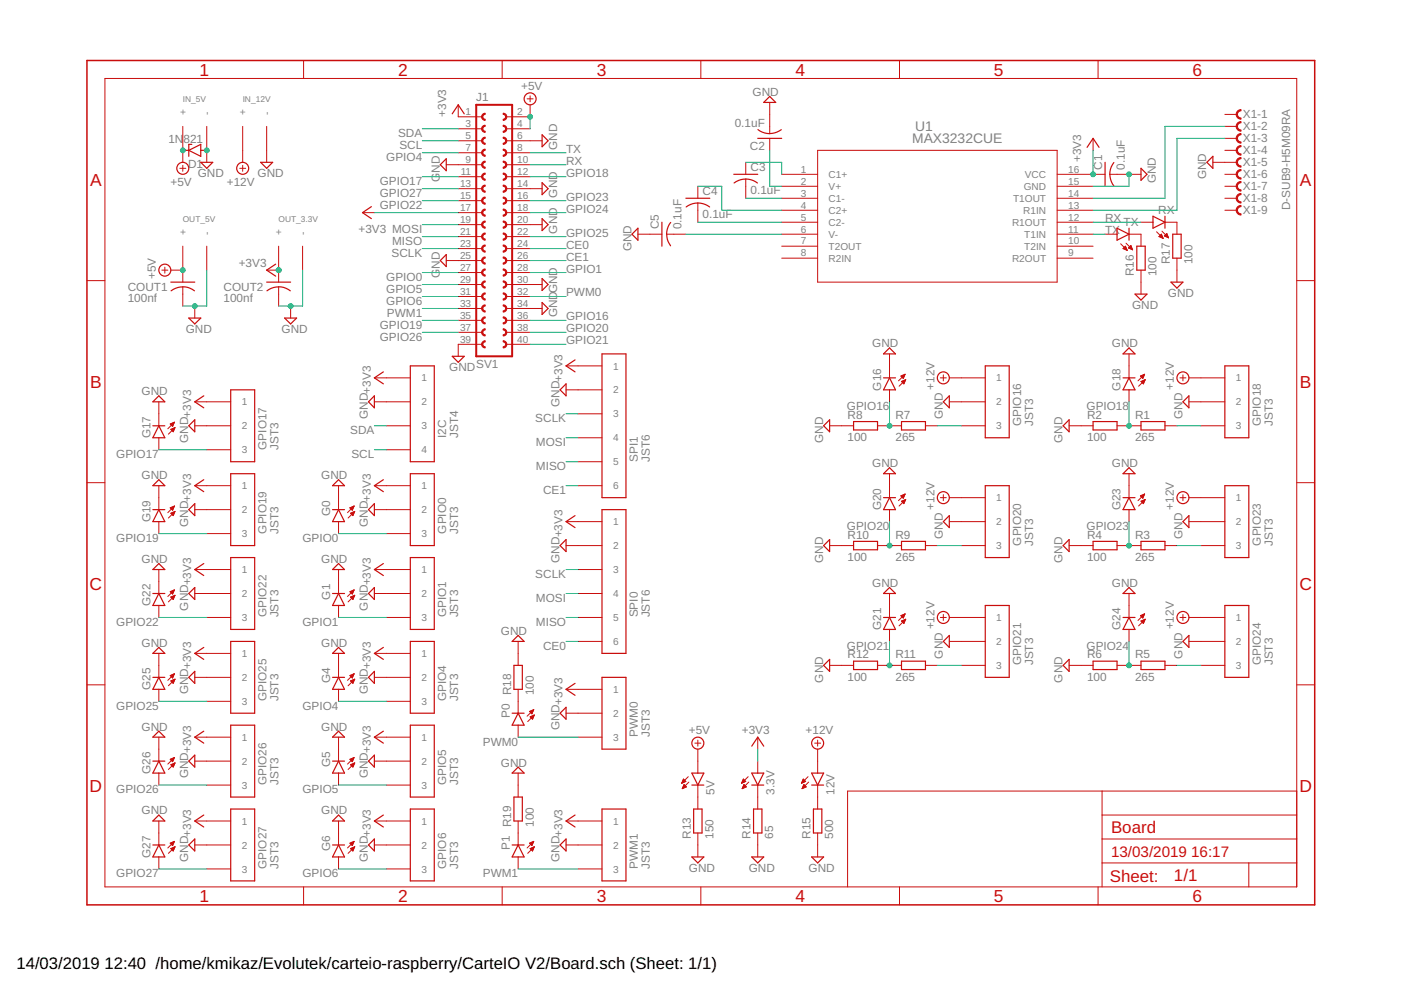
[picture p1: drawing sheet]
<svg xmlns="http://www.w3.org/2000/svg" width="297mm" height="210mm" viewBox="0 0 297 210" stroke-linecap="round" stroke-linejoin="round" font-family="sans-serif">
<defs><g id="words">
<g font-size="3.7" fill="#c90d0c">
<text x="42.3" y="16">1</text>
<text x="84.4" y="16">2</text>
<text x="126.5" y="16">3</text>
<text x="168.6" y="16">4</text>
<text x="210.7" y="16">5</text>
<text x="252.9" y="16">6</text>
<text x="19.1" y="39.4">A</text>
<text x="275.6" y="39.4">A</text>
<text x="19.1" y="82.2">B</text>
<text x="275.6" y="82.2">B</text>
<text x="19" y="125.1">C</text>
<text x="275.5" y="125.1">C</text>
<text x="19" y="167.9">D</text>
<text x="275.5" y="167.9">D</text>
<text x="42.3" y="191.2">1</text>
<text x="84.4" y="191.2">2</text>
<text x="126.5" y="191.2">3</text>
<text x="168.6" y="191.2">4</text>
<text x="210.7" y="191.2">5</text>
<text x="252.9" y="191.2">6</text>
</g>
<g font-size="3.6" fill="#c90d0c">
<text x="235.6" y="176.6">Board</text>
<text x="235.3" y="186.9">Sheet:</text>
<text x="248.9" y="186.8">1/1</text>
</g>
<g font-size="3.5">
<text x="3.5" y="205.4">14/03/2019</text>
<text x="22.2" y="205.4">12:40 /home/kmikaz/Evolutek/carteio-raspberry/CarteIO V2/Board.sch (Sheet: 1/1)</text>
</g>
<g font-size="3.2" fill="#c90d0c">
<text x="235.6" y="181.7">13/03/2019</text>
<text x="252.6" y="181.7">16:17</text>
</g>
<g font-size="2.9" fill="#808080">
<text x="194.1" y="27.8">U1</text>
<text x="193.4" y="30.4">MAX3232CUE</text>
</g>
<g font-size="2.5" fill="#808080">
<text x="101" y="21.5">J1</text>
<text x="110.5" y="19.1">+5V</text>
<text x="159.5" y="20.3">GND</text>
<text x="84.4" y="29.1">SDA</text>
<text x="94.6" y="24.8" transform="rotate(-90 94.6 24.8)">+3V3</text>
<text x="155.8" y="26.9">0.1uF</text>
<text x="263.5" y="25">X1-1</text>
<text x="263.5" y="27.6">X1-2</text>
<text x="35.7" y="30.2">1N</text>
<text x="38.9" y="30.2">821</text>
<text x="39.9" y="35.6">D1</text>
<text x="81.9" y="34.2">GPIO4</text>
<text x="84.7" y="31.6">SCL</text>
<text x="118.1" y="31.7" transform="rotate(-90 118.1 31.7)">GND</text>
<text x="120" y="32.4">TX</text>
<text x="120" y="34.9">RX</text>
<text x="159" y="31.7">C2</text>
<text x="229.2" y="34.4" transform="rotate(-90 229.2 34.4)">+3V3</text>
<text x="233.7" y="35.9" transform="rotate(-90 233.7 35.9)">C1</text>
<text x="238.5" y="35.9" transform="rotate(-90 238.5 35.9)">0.1uF</text>
<text x="263.5" y="30.1">X1-3</text>
<text x="263.5" y="32.6">X1-4</text>
<text x="263.5" y="35.2">X1-5</text>
<text x="36.1" y="39.4">+5V</text>
<text x="41.9" y="37.6">GND</text>
<text x="48.1" y="39.4">+12V</text>
<text x="54.6" y="37.6">GND</text>
<text x="80.5" y="39.2">GPIO17</text>
<text x="80.5" y="41.8">GPIO27</text>
<text x="93.2" y="38.6" transform="rotate(-90 93.2 38.6)">GND</text>
<text x="118.1" y="41.9" transform="rotate(-90 118.1 41.9)">GND</text>
<text x="120" y="37.5">GPIO18</text>
<text x="149" y="41.4">C4</text>
<text x="159.1" y="41.1">0.1uF</text>
<text x="159.1" y="36.3">C3</text>
<text x="245.1" y="38.9" transform="rotate(-90 245.1 38.9)">GND</text>
<text x="255.8" y="38.1" transform="rotate(-90 255.8 38.1)">GND</text>
<text x="263.5" y="37.7">X1-6</text>
<text x="263.5" y="40.3">X1-7</text>
<text x="80.5" y="44.3">GPIO22</text>
<text x="120" y="42.5">GPIO23</text>
<text x="120" y="45.1">GPIO24</text>
<text x="149" y="46.2">0.1uF</text>
<text x="234.3" y="47.1">RX</text>
<text x="238.2" y="47.9">TX</text>
<text x="245.6" y="45.3">RX</text>
<text x="263.5" y="42.8">X1-8</text>
<text x="263.5" y="45.3">X1-9</text>
<text x="273.5" y="44.6" transform="rotate(-90 273.5 44.6)">D-SUB9-H5M09RA</text>
<text x="76" y="49.4">+3V3 MOSI</text>
<text x="83.2" y="51.9">MISO</text>
<text x="118.1" y="49.5" transform="rotate(-90 118.1 49.5)">GND</text>
<text x="120" y="50.2">GPIO25</text>
<text x="120" y="52.7">CE0</text>
<text x="133.9" y="53.3" transform="rotate(-90 133.9 53.3)">GND</text>
<text x="139.7" y="48.6" transform="rotate(-90 139.7 48.6)">C5</text>
<text x="144.5" y="48.6" transform="rotate(-90 144.5 48.6)">0.1uF</text>
<text x="234.3" y="49.7">TX</text>
<text x="33" y="59.2" transform="rotate(-90 33 59.2)">+5V</text>
<text x="50.6" y="56.5">+3V3</text>
<text x="81.9" y="59.6">GPIO0</text>
<text x="83" y="54.5">SCLK</text>
<text x="93.2" y="58.9" transform="rotate(-90 93.2 58.9)">GND</text>
<text x="120" y="57.8">GPIO1</text>
<text x="120" y="55.2">CE1</text>
<text x="240.4" y="58.5" transform="rotate(-90 240.4 58.5)">R16</text>
<text x="245.2" y="58.5" transform="rotate(-90 245.2 58.5)">100</text>
<text x="248" y="56" transform="rotate(-90 248 56)">R17</text>
<text x="252.8" y="56" transform="rotate(-90 252.8 56)">100</text>
<text x="27.1" y="64">100nf</text>
<text x="27.1" y="61.7">COUT1</text>
<text x="47.4" y="64">100nf</text>
<text x="47.4" y="61.7">COUT2</text>
<text x="81.9" y="62.1">GPIO5</text>
<text x="81.9" y="64.6">GPIO6</text>
<text x="120" y="62.9">PWM0</text>
<text x="240" y="65.5">GND</text>
<text x="247.6" y="63">GND</text>
<text x="39.4" y="70.6">GND</text>
<text x="59.7" y="70.6">GND</text>
<text x="80.5" y="69.7">GPIO19</text>
<text x="82.1" y="67.2">PWM1</text>
<text x="118.1" y="67.3" transform="rotate(-90 118.1 67.3)">GNDGND</text>
<text x="120" y="67.9">GPIO16</text>
<text x="120" y="70.5">GPIO20</text>
<text x="80.5" y="72.3">GPIO26</text>
<text x="120" y="73">GPIO21</text>
<text x="184.9" y="73.6">GND</text>
<text x="235.7" y="73.6">GND</text>
<text x="30" y="83.8">GND</text>
<text x="78.6" y="83.5" transform="rotate(-90 78.6 83.5)">+3V3</text>
<text x="95.3" y="78.7">GND</text>
<text x="101" y="78.1">SV1</text>
<text x="119.3" y="81" transform="rotate(-90 119.3 81)">+3V3</text>
<text x="186.8" y="82.8" transform="rotate(-90 186.8 82.8)">G16</text>
<text x="198.1" y="82.7" transform="rotate(-90 198.1 82.7)">+12V</text>
<text x="237.6" y="82.8" transform="rotate(-90 237.6 82.8)">G18</text>
<text x="248.9" y="82.7" transform="rotate(-90 248.9 82.7)">+12V</text>
<text x="40.5" y="88.6" transform="rotate(-90 40.5 88.6)">+3V3</text>
<text x="78" y="88.8" transform="rotate(-90 78 88.8)">GND</text>
<text x="113.5" y="89.5">SCLK</text>
<text x="118.6" y="86.3" transform="rotate(-90 118.6 86.3)">GND</text>
<text x="179.6" y="87">GPIO16</text>
<text x="179.7" y="88.8">R8</text>
<text x="189.9" y="88.8">R7</text>
<text x="199.9" y="88.8" transform="rotate(-90 199.9 88.8)">GND</text>
<text x="230.4" y="87">GPIO18</text>
<text x="230.5" y="88.8">R2</text>
<text x="240.6" y="88.8">R1</text>
<text x="250.7" y="88.8" transform="rotate(-90 250.7 88.8)">GND</text>
<text x="31.9" y="93" transform="rotate(-90 31.9 93)">G17</text>
<text x="39.9" y="93.9" transform="rotate(-90 39.9 93.9)">GND</text>
<text x="56.5" y="95.4" transform="rotate(-90 56.5 95.4)">GPIO17</text>
<text x="59.1" y="95.4" transform="rotate(-90 59.1 95.4)">JST3</text>
<text x="74.2" y="92.1">SDA</text>
<text x="94.6" y="92.8" transform="rotate(-90 94.6 92.8)">I2C</text>
<text x="97.2" y="92.8" transform="rotate(-90 97.2 92.8)">JST4</text>
<text x="113.6" y="94.6">MOSI</text>
<text x="174.5" y="93.9" transform="rotate(-90 174.5 93.9)">GND</text>
<text x="179.7" y="93.6">100</text>
<text x="189.9" y="93.6">265</text>
<text x="216.5" y="90.3" transform="rotate(-90 216.5 90.3)">GPIO16</text>
<text x="219.1" y="90.3" transform="rotate(-90 219.1 90.3)">JST3</text>
<text x="225.3" y="93.9" transform="rotate(-90 225.3 93.9)">GND</text>
<text x="230.5" y="93.6">100</text>
<text x="240.6" y="93.6">265</text>
<text x="267.3" y="90.3" transform="rotate(-90 267.3 90.3)">GPIO18</text>
<text x="269.9" y="90.3" transform="rotate(-90 269.9 90.3)">JST3</text>
<text x="24.7" y="97.1">GPIO17</text>
<text x="30" y="101.6">GND</text>
<text x="68.1" y="101.6">GND</text>
<text x="74.5" y="97.1">SCL</text>
<text x="113.6" y="99.7">MISO</text>
<text x="135.3" y="97.9" transform="rotate(-90 135.3 97.9)">SPI1</text>
<text x="137.8" y="97.9" transform="rotate(-90 137.8 97.9)">JST6</text>
<text x="184.9" y="99">GND</text>
<text x="235.7" y="99">GND</text>
<text x="40.5" y="106.3" transform="rotate(-90 40.5 106.3)">+3V3</text>
<text x="78.6" y="106.3" transform="rotate(-90 78.6 106.3)">+3V3</text>
<text x="115.1" y="104.8">CE1</text>
<text x="31.9" y="110.7" transform="rotate(-90 31.9 110.7)">G19</text>
<text x="39.9" y="111.7" transform="rotate(-90 39.9 111.7)">GND</text>
<text x="56.5" y="113.1" transform="rotate(-90 56.5 113.1)">GPIO19</text>
<text x="59.1" y="113.1" transform="rotate(-90 59.1 113.1)">JST3</text>
<text x="70" y="109.3" transform="rotate(-90 70 109.3)">G0</text>
<text x="78" y="111.7" transform="rotate(-90 78 111.7)">GND</text>
<text x="94.6" y="113.1" transform="rotate(-90 94.6 113.1)">GPIO0</text>
<text x="97.2" y="113.1" transform="rotate(-90 97.2 113.1)">JST3</text>
<text x="119.3" y="114" transform="rotate(-90 119.3 114)">+3V3</text>
<text x="179.6" y="112.4">GPIO20</text>
<text x="186.8" y="108.2" transform="rotate(-90 186.8 108.2)">G20</text>
<text x="198.1" y="108.1" transform="rotate(-90 198.1 108.1)">+12V</text>
<text x="230.4" y="112.4">GPIO23</text>
<text x="237.6" y="108.2" transform="rotate(-90 237.6 108.2)">G23</text>
<text x="248.9" y="108.1" transform="rotate(-90 248.9 108.1)">+12V</text>
<text x="24.7" y="114.9">GPIO19</text>
<text x="30" y="119.4">GND</text>
<text x="64.1" y="114.9">GPIO0</text>
<text x="68.1" y="119.4">GND</text>
<text x="118.6" y="119.3" transform="rotate(-90 118.6 119.3)">GND</text>
<text x="174.5" y="119.3" transform="rotate(-90 174.5 119.3)">GND</text>
<text x="179.7" y="119">100</text>
<text x="179.7" y="114.2">R10</text>
<text x="189.9" y="119">265</text>
<text x="189.9" y="114.2">R9</text>
<text x="199.9" y="114.2" transform="rotate(-90 199.9 114.2)">GND</text>
<text x="216.5" y="115.7" transform="rotate(-90 216.5 115.7)">GPIO20</text>
<text x="219.1" y="115.7" transform="rotate(-90 219.1 115.7)">JST3</text>
<text x="225.3" y="119.3" transform="rotate(-90 225.3 119.3)">GND</text>
<text x="230.5" y="119">100</text>
<text x="230.5" y="114.2">R4</text>
<text x="240.6" y="119">265</text>
<text x="240.6" y="114.2">R3</text>
<text x="250.7" y="114.2" transform="rotate(-90 250.7 114.2)">GND</text>
<text x="267.3" y="115.7" transform="rotate(-90 267.3 115.7)">GPIO23</text>
<text x="269.9" y="115.7" transform="rotate(-90 269.9 115.7)">JST3</text>
<text x="40.5" y="124.1" transform="rotate(-90 40.5 124.1)">+3V3</text>
<text x="78.6" y="124.1" transform="rotate(-90 78.6 124.1)">+3V3</text>
<text x="113.5" y="122.5">SCLK</text>
<text x="184.9" y="124.4">GND</text>
<text x="235.7" y="124.4">GND</text>
<text x="31.9" y="128.5" transform="rotate(-90 31.9 128.5)">G22</text>
<text x="39.9" y="129.5" transform="rotate(-90 39.9 129.5)">GND</text>
<text x="56.5" y="130.9" transform="rotate(-90 56.5 130.9)">GPIO22</text>
<text x="59.1" y="130.9" transform="rotate(-90 59.1 130.9)">JST3</text>
<text x="70" y="127.1" transform="rotate(-90 70 127.1)">G1</text>
<text x="78" y="129.5" transform="rotate(-90 78 129.5)">GND</text>
<text x="94.6" y="130.9" transform="rotate(-90 94.6 130.9)">GPIO1</text>
<text x="97.2" y="130.9" transform="rotate(-90 97.2 130.9)">JST3</text>
<text x="113.6" y="127.6">MOSI</text>
<text x="135.3" y="130.9" transform="rotate(-90 135.3 130.9)">SPI0</text>
<text x="137.8" y="130.9" transform="rotate(-90 137.8 130.9)">JST6</text>
<text x="24.7" y="132.7">GPIO22</text>
<text x="30" y="137.1">GND</text>
<text x="64.1" y="132.7">GPIO1</text>
<text x="68.1" y="137.1">GND</text>
<text x="106.2" y="134.6">GND</text>
<text x="113.6" y="132.7">MISO</text>
<text x="115.1" y="137.8">CE0</text>
<text x="179.6" y="137.8">GPIO21</text>
<text x="186.8" y="133.6" transform="rotate(-90 186.8 133.6)">G21</text>
<text x="198.1" y="133.4" transform="rotate(-90 198.1 133.4)">+12V</text>
<text x="230.4" y="137.8">GPIO24</text>
<text x="237.6" y="133.6" transform="rotate(-90 237.6 133.6)">G24</text>
<text x="248.9" y="133.4" transform="rotate(-90 248.9 133.4)">+12V</text>
<text x="40.5" y="141.9" transform="rotate(-90 40.5 141.9)">+3V3</text>
<text x="78.6" y="141.9" transform="rotate(-90 78.6 141.9)">+3V3</text>
<text x="179.7" y="139.6">R12</text>
<text x="189.9" y="139.6">R11</text>
<text x="199.9" y="139.6" transform="rotate(-90 199.9 139.6)">GND</text>
<text x="216.5" y="141.1" transform="rotate(-90 216.5 141.1)">GPIO21</text>
<text x="219.1" y="141.1" transform="rotate(-90 219.1 141.1)">JST3</text>
<text x="230.5" y="139.6">R6</text>
<text x="240.6" y="139.6">R5</text>
<text x="250.7" y="139.6" transform="rotate(-90 250.7 139.6)">GND</text>
<text x="267.3" y="141.1" transform="rotate(-90 267.3 141.1)">GPIO24</text>
<text x="269.9" y="141.1" transform="rotate(-90 269.9 141.1)">JST3</text>
<text x="31.9" y="146.3" transform="rotate(-90 31.9 146.3)">G25</text>
<text x="39.9" y="147.2" transform="rotate(-90 39.9 147.2)">GND</text>
<text x="56.5" y="148.7" transform="rotate(-90 56.5 148.7)">GPIO25</text>
<text x="59.1" y="148.7" transform="rotate(-90 59.1 148.7)">JST3</text>
<text x="70" y="144.9" transform="rotate(-90 70 144.9)">G4</text>
<text x="78" y="147.2" transform="rotate(-90 78 147.2)">GND</text>
<text x="94.6" y="148.7" transform="rotate(-90 94.6 148.7)">GPIO4</text>
<text x="97.2" y="148.7" transform="rotate(-90 97.2 148.7)">JST3</text>
<text x="108.4" y="147.4" transform="rotate(-90 108.4 147.4)">R18</text>
<text x="113.2" y="147.4" transform="rotate(-90 113.2 147.4)">100</text>
<text x="119.3" y="149.5" transform="rotate(-90 119.3 149.5)">+3V3</text>
<text x="174.5" y="144.7" transform="rotate(-90 174.5 144.7)">GND</text>
<text x="179.7" y="144.4">100</text>
<text x="189.9" y="144.4">265</text>
<text x="225.3" y="144.7" transform="rotate(-90 225.3 144.7)">GND</text>
<text x="230.5" y="144.4">100</text>
<text x="240.6" y="144.4">265</text>
<text x="24.7" y="150.5">GPIO25</text>
<text x="30" y="154.9">GND</text>
<text x="64.1" y="150.5">GPIO4</text>
<text x="68.1" y="154.9">GND</text>
<text x="108.1" y="152.2" transform="rotate(-90 108.1 152.2)">P0</text>
<text x="118.6" y="154.9" transform="rotate(-90 118.6 154.9)">GND</text>
<text x="146" y="155.7">+5V</text>
<text x="157.3" y="155.5">+3V3</text>
<text x="170.8" y="155.7">+12V</text>
<text x="40.5" y="159.7" transform="rotate(-90 40.5 159.7)">+3V3</text>
<text x="78.6" y="159.7" transform="rotate(-90 78.6 159.7)">+3V3</text>
<text x="102.4" y="158.1">PWM0</text>
<text x="135.3" y="156.3" transform="rotate(-90 135.3 156.3)">PWM0</text>
<text x="137.8" y="156.3" transform="rotate(-90 137.8 156.3)">JST3</text>
<text x="31.9" y="164.1" transform="rotate(-90 31.9 164.1)">G26</text>
<text x="39.9" y="165" transform="rotate(-90 39.9 165)">GND</text>
<text x="56.5" y="166.5" transform="rotate(-90 56.5 166.5)">GPIO26</text>
<text x="59.1" y="166.5" transform="rotate(-90 59.1 166.5)">JST3</text>
<text x="70" y="162.7" transform="rotate(-90 70 162.7)">G5</text>
<text x="78" y="165" transform="rotate(-90 78 165)">GND</text>
<text x="94.6" y="166.5" transform="rotate(-90 94.6 166.5)">GPIO5</text>
<text x="97.2" y="166.5" transform="rotate(-90 97.2 166.5)">JST3</text>
<text x="106.2" y="162.5">GND</text>
<text x="24.7" y="168.2">GPIO26</text>
<text x="30" y="172.7">GND</text>
<text x="64.1" y="168.2">GPIO5</text>
<text x="68.1" y="172.7">GND</text>
<text x="151.5" y="168.5" transform="rotate(-90 151.5 168.5)">5V</text>
<text x="164.2" y="168.5" transform="rotate(-90 164.2 168.5)">3.3V</text>
<text x="176.9" y="168.5" transform="rotate(-90 176.9 168.5)">12V</text>
<text x="40.5" y="177.4" transform="rotate(-90 40.5 177.4)">+3V3</text>
<text x="78.6" y="177.4" transform="rotate(-90 78.6 177.4)">+3V3</text>
<text x="108.4" y="175.3" transform="rotate(-90 108.4 175.3)">R19</text>
<text x="113.2" y="175.3" transform="rotate(-90 113.2 175.3)">100</text>
<text x="119.3" y="177.4" transform="rotate(-90 119.3 177.4)">+3V3</text>
<text x="146.5" y="177.9" transform="rotate(-90 146.5 177.9)">R13</text>
<text x="151.3" y="177.9" transform="rotate(-90 151.3 177.9)">150</text>
<text x="159.2" y="177.9" transform="rotate(-90 159.2 177.9)">R14</text>
<text x="164" y="177.9" transform="rotate(-90 164 177.9)">65</text>
<text x="171.9" y="177.9" transform="rotate(-90 171.9 177.9)">R15</text>
<text x="176.7" y="177.9" transform="rotate(-90 176.7 177.9)">500</text>
<text x="31.9" y="181.8" transform="rotate(-90 31.9 181.8)">G27</text>
<text x="39.9" y="182.8" transform="rotate(-90 39.9 182.8)">GND</text>
<text x="56.5" y="184.2" transform="rotate(-90 56.5 184.2)">GPIO27</text>
<text x="59.1" y="184.2" transform="rotate(-90 59.1 184.2)">JST3</text>
<text x="70" y="180.4" transform="rotate(-90 70 180.4)">G6</text>
<text x="78" y="182.8" transform="rotate(-90 78 182.8)">GND</text>
<text x="94.6" y="184.2" transform="rotate(-90 94.6 184.2)">GPIO6</text>
<text x="97.2" y="184.2" transform="rotate(-90 97.2 184.2)">JST3</text>
<text x="108.1" y="180.2" transform="rotate(-90 108.1 180.2)">P1</text>
<text x="118.6" y="182.8" transform="rotate(-90 118.6 182.8)">GND</text>
<text x="135.3" y="184.2" transform="rotate(-90 135.3 184.2)">PWM1</text>
<text x="137.8" y="184.2" transform="rotate(-90 137.8 184.2)">JST3</text>
<text x="146" y="184.9">GND</text>
<text x="158.7" y="184.9">GND</text>
<text x="171.4" y="184.9">GND</text>
<text x="24.7" y="186">GPIO27</text>
<text x="64.1" y="186">GPIO6</text>
<text x="102.4" y="186">PWM1</text>
</g>
<g font-size="2.1" fill="#808080">
<text x="39.5" y="24.5" transform="rotate(-90 39.5 24.5)">+</text>
<text x="44.6" y="24.5" transform="rotate(-90 44.6 24.5)">-</text>
<text x="52.2" y="24.5" transform="rotate(-90 52.2 24.5)">+</text>
<text x="57.3" y="24.5" transform="rotate(-90 57.3 24.5)">-</text>
<text x="98.7" y="24.4">1</text>
<text x="98.7" y="26.9">3</text>
<text x="98.7" y="29.5">5</text>
<text x="109.7" y="24.4">2</text>
<text x="109.7" y="26.9">4</text>
<text x="109.7" y="29.5">6</text>
<text x="98.7" y="32">7</text>
<text x="98.7" y="34.6">9</text>
<text x="109.7" y="32">8</text>
<text x="109.7" y="34.6">10</text>
<text x="97.5" y="39.6">13</text>
<text x="97.7" y="37.1">11</text>
<text x="109.7" y="37.1">12</text>
<text x="109.7" y="39.6">14</text>
<text x="169.8" y="36.6">1</text>
<text x="169.8" y="39.1">2</text>
<text x="169.8" y="41.7">3</text>
<text x="175.7" y="37.7">C1+</text>
<text x="175.7" y="40.3">V+</text>
<text x="217.1" y="40.3">GND</text>
<text x="217.3" y="37.7">VCC</text>
<text x="226.5" y="41.7">14</text>
<text x="226.5" y="39.1">15</text>
<text x="226.5" y="36.6">16</text>
<text x="97.5" y="42.2">15</text>
<text x="97.5" y="44.7">17</text>
<text x="97.5" y="47.3">19</text>
<text x="109.7" y="42.2">16</text>
<text x="109.7" y="44.7">18</text>
<text x="109.7" y="47.3">20</text>
<text x="169.8" y="44.2">4</text>
<text x="169.8" y="46.8">5</text>
<text x="175.7" y="42.8">C1-</text>
<text x="175.7" y="45.3">C2+</text>
<text x="175.7" y="47.9">C2-</text>
<text x="214.6" y="47.9">R1OUT</text>
<text x="214.8" y="42.8">T1OUT</text>
<text x="216.9" y="45.3">R1IN</text>
<text x="226.5" y="46.8">12</text>
<text x="226.5" y="44.2">13</text>
<text x="39.5" y="49.9" transform="rotate(-90 39.5 49.9)">+</text>
<text x="44.6" y="49.9" transform="rotate(-90 44.6 49.9)">-</text>
<text x="59.8" y="49.9" transform="rotate(-90 59.8 49.9)">+</text>
<text x="64.9" y="49.9" transform="rotate(-90 64.9 49.9)">-</text>
<text x="97.5" y="49.8">21</text>
<text x="97.5" y="52.3">23</text>
<text x="109.7" y="49.8">22</text>
<text x="109.7" y="52.3">24</text>
<text x="169.8" y="49.3">6</text>
<text x="169.8" y="51.8">7</text>
<text x="175.7" y="50.4">V-</text>
<text x="175.7" y="53">T2OUT</text>
<text x="217.2" y="53">T2IN</text>
<text x="217.2" y="50.4">T1IN</text>
<text x="226.5" y="51.8">10</text>
<text x="226.5" y="49.3">11</text>
<text x="97.5" y="54.9">25</text>
<text x="97.5" y="57.4">27</text>
<text x="97.5" y="60">29</text>
<text x="109.7" y="54.9">26</text>
<text x="109.7" y="57.4">28</text>
<text x="109.7" y="60">30</text>
<text x="169.8" y="54.4">8</text>
<text x="175.7" y="55.5">R2IN</text>
<text x="214.6" y="55.5">R2OUT</text>
<text x="226.5" y="54.4">9</text>
<text x="97.5" y="62.5">31</text>
<text x="97.5" y="65">33</text>
<text x="109.7" y="62.5">32</text>
<text x="109.7" y="65">34</text>
<text x="97.5" y="67.6">35</text>
<text x="97.5" y="70.1">37</text>
<text x="109.7" y="67.6">36</text>
<text x="109.7" y="70.1">38</text>
<text x="97.5" y="72.7">39</text>
<text x="109.7" y="72.7">40</text>
<text x="89.3" y="80.9">1</text>
<text x="130" y="78.3">1</text>
<text x="130" y="83.4">2</text>
<text x="211.2" y="80.9">1</text>
<text x="262" y="80.9">1</text>
<text x="51.2" y="86">1</text>
<text x="89.3" y="86">2</text>
<text x="130" y="88.5">3</text>
<text x="211.2" y="86">2</text>
<text x="262" y="86">2</text>
<text x="51.2" y="91">2</text>
<text x="89.3" y="91">3</text>
<text x="130" y="93.6">4</text>
<text x="211.2" y="91">3</text>
<text x="262" y="91">3</text>
<text x="51.2" y="96.1">3</text>
<text x="89.3" y="96.1">4</text>
<text x="130" y="98.7">5</text>
<text x="51.2" y="103.7">1</text>
<text x="89.3" y="103.7">1</text>
<text x="130" y="103.7">6</text>
<text x="211.2" y="106.3">1</text>
<text x="262" y="106.3">1</text>
<text x="51.2" y="108.8">2</text>
<text x="51.2" y="113.9">3</text>
<text x="89.3" y="108.8">2</text>
<text x="89.3" y="113.9">3</text>
<text x="130" y="111.4">1</text>
<text x="211.2" y="111.4">2</text>
<text x="262" y="111.4">2</text>
<text x="130" y="116.4">2</text>
<text x="211.2" y="116.4">3</text>
<text x="262" y="116.4">3</text>
<text x="51.2" y="121.5">1</text>
<text x="89.3" y="121.5">1</text>
<text x="130" y="121.5">3</text>
<text x="51.2" y="126.6">2</text>
<text x="51.2" y="131.7">3</text>
<text x="89.3" y="126.6">2</text>
<text x="89.3" y="131.7">3</text>
<text x="130" y="126.6">4</text>
<text x="130" y="131.7">5</text>
<text x="211.2" y="131.7">1</text>
<text x="262" y="131.7">1</text>
<text x="130" y="136.8">6</text>
<text x="211.2" y="136.8">2</text>
<text x="262" y="136.8">2</text>
<text x="51.2" y="139.3">1</text>
<text x="89.3" y="139.3">1</text>
<text x="211.2" y="141.8">3</text>
<text x="262" y="141.8">3</text>
<text x="51.2" y="144.4">2</text>
<text x="51.2" y="149.4">3</text>
<text x="89.3" y="144.4">2</text>
<text x="89.3" y="149.4">3</text>
<text x="130" y="146.9">1</text>
<text x="130" y="152">2</text>
<text x="51.2" y="157.1">1</text>
<text x="89.3" y="157.1">1</text>
<text x="130" y="157.1">3</text>
<text x="51.2" y="162.1">2</text>
<text x="51.2" y="167.2">3</text>
<text x="89.3" y="162.1">2</text>
<text x="89.3" y="167.2">3</text>
<text x="51.2" y="174.8">1</text>
<text x="51.2" y="179.9">2</text>
<text x="89.3" y="174.8">1</text>
<text x="89.3" y="179.9">2</text>
<text x="130" y="174.8">1</text>
<text x="130" y="179.9">2</text>
<text x="51.2" y="185">3</text>
<text x="89.3" y="185">3</text>
<text x="130" y="185">3</text>
</g>
<g font-size="1.8" fill="#808080">
<text x="38.8" y="21.7">IN_5V</text>
<text x="51.5" y="21.7">IN_12V</text>
<text x="38.8" y="47.1">OUT_5V</text>
<text x="59.1" y="47.1">OUT_3.3V</text>
</g>
</g></defs>
<g fill="none" stroke="#c90d0c" stroke-width=".21">
<path d="M22.2 16.6h252.7v171.4h-252.7zM64.4 12.8v3.8M106.5 12.8v3.8M148.6 12.8v3.8M190.7 12.8v3.8M232.8 12.8v3.8M38.1 35.7h1.3M38.8 26.8v7.6M38.8 35.1v1.2M43.8 26.8v7.6M50.8 35.7h1.3M51.5 26.8v7.6"/>
<path d="M51.5 35.1v1.2M56.5 26.8v7.6M94.6 34.9h7.6M97.2 22.2v2.6h5M97.2 29.8h5M97.2 27.3h5M97.2 32.4h5M97.2 37.5h5M107.3 29.8h7.6M107.3 27.3h5.1M107.3 32.4h5.1M107.3 34.9h5.1"/>
<path d="M107.3 37.5h5.1M111.8 21h1.2M112.4 20.3v1.3M112.4 22.2v2.6h-5.1M148 39.5v2.5M158.1 34.4v2.6M158.1 38v4M163.2 21.7v6.6M163.2 29.3v2.6M165.7 37h7.7M165.7 39.5h7.7M173.4 31.9h50.7v27.9h-50.7z"/>
<path d="M224.1 37h10.2M224.1 39.5h7.7M231.8 29.3v2.6M235.3 37h6.6M257.2 34.4h5M259.7 37h2.5M259.7 31.9h2.5M259.7 39.5h2.5M259.7 24.3h2.5M259.7 26.8h2.5M259.7 29.3h2.5M18.4 59.5h3.8"/>
<path d="M34.3 57.3h1.3M34.9 56.6v1.3M36.2 57.3h2.6M38.8 52.2v7.6M43.8 52.2v5.1M56.5 57.3h2.6M59.1 52.2v7.6M64.2 52.2v5.1M76.9 45.1h2.5M94.6 55.2h7.6M97.2 40h5M97.2 42.5h5"/>
<path d="M97.2 45.1h5M97.2 47.6h5M97.2 50.2h5M97.2 52.7h5M97.2 57.8h5M107.3 40h7.6M107.3 42.5h5.1M107.3 45.1h5.1M107.3 47.6h7.6M107.3 50.2h5.1M107.3 52.7h5.1M107.3 55.2h5.1"/>
<path d="M107.3 57.8h5.1M135.3 49.7h5M141.4 49.7h4M148 43.1v4M165.7 42h7.7M165.7 44.6h7.7M165.7 47.1h7.7M165.7 49.7h7.7M165.7 52.2h7.7M165.7 54.7h7.7M224.1 42h7.7M224.1 44.6h7.7"/>
<path d="M224.1 47.1h7.7M224.1 49.7h7.7M224.1 52.2h7.7M224.1 54.7h7.7M234.3 49.7h2.5M237.6 51.7l1.4 1.4M238.1 52.7l.5-.5 .4 .9zM238.1 52.7h.7M238.3 52.6h.5M238.3 52.8h.6M238.4 52.4h.3M238.5 52.3h.2"/>
<path d="M238.6 52.9h.3M238.7 51.6l1.4 1.4M238.9 53h.1M239.2 52.6l.9 .4M239.3 52.6h.7M239.4 49.7h2.5v2.5M239.4 52.4h.5M239.5 52.7h.5M239.5 52.3h.4M239.6 52.2h.2M239.8 52.8h.3M239.8 52.1l-.6 .5"/>
<path d="M239.8 52.1l.3 .9M239.8 52.1h.1M240 52.9h.1M241.9 47.1h2.6M241.9 57.3v5.1M245.2 49.1l1.4 1.4M245.7 50.2l.9 .3M245.7 50.1h.7M245.9 50h.5M246 50.2h.5M246 49.9h.3M246.1 49.8h.2"/>
<path d="M246.2 49.7l-.5 .5M246.2 49.7l.4 .8M246.2 50.4h.3M246.2 49.7h.1M246.4 49l1.4 1.4M246.5 50.5h.1M246.9 50h.7M247 47.1h2.5v2.6M247 49.9h.5M247.1 50.1h.5M247.1 49.8h.4M247.2 49.7h.2"/>
<path d="M247.4 49.5l-.5 .5 .9 .4M247.4 49.5l.4 .9M247.4 49.5v.1M247.4 50.2h.3M247.7 50.4h.1M249.5 54.7v5.1M259.7 42h2.5M259.7 44.6h2.5M274.9 59.5h3.8M38.8 60.8v4.1M41.3 64.9v2.5M59.1 60.8v4.1"/>
<path d="M61.6 64.9v2.5M97.2 60.3h5M97.2 62.9h5M97.2 65.4h5M97.2 67.9h5M97.2 70.5h5M102.2 73h-5v2.5M107.3 60.3h7.6M107.3 62.9h5.1M107.3 65.4h7.6M107.3 67.9h5.1M107.3 70.5h5.1"/>
<path d="M107.3 73h5.1M120 77.6h7.6M188.6 75v5.1M191 79.7l.9-.3-.4 .8zM191.1 79.8h.6M191.1 79.7h.6M191.2 79.9h.4M191.4 79.6h.4M191.7 79.4h.2M191.9 79.4l-1.4 1.4M200 79.5v1.3M239.4 75v5.1"/>
<path d="M241.8 79.7l.9-.3-.4 .8zM241.9 79.8h.6M241.9 79.7h.6M242 79.9h.4M242.2 79.6h.4M242.5 79.4h.1M242.7 79.4l-1.4 1.4M250.8 79.5v1.3M33.7 85.2v5.1M33.7 92.8v2.6M36.1 89.9l.9-.4-.4 .9zM36.1 89.9h.7"/>
<path d="M36.2 91l.9-.3-.4 .8zM36.2 90.1h.5M36.3 91h.7M36.3 89.8h.6M36.3 91.1h.6M36.4 90.2h.3M36.4 91.3h.5M36.5 90.3h.1M36.5 90.9h.5M36.6 91.4h.2M36.6 89.7h.3M36.7 91.5h.1"/>
<path d="M36.8 90.8h.2M36.9 89.6h.1M37 89.5l-1.4 1.4M37.1 90.7l-1.4 1.4M41.3 85.2h7.6M41.3 90.3h7.6M43.8 95.4h5.1M79.4 80.1h7.6M79.4 85.2h7.6M81.9 90.3h5.1M81.9 95.4h5.1M120 82.7h7.6"/>
<path d="M122.6 87.7h5M122.6 92.8h5M122.6 97.9h5M175.9 90.3h5.1M186.1 90.3h5M188.6 82.7v2.5M191.1 80.9h.8M191.1 80.9l.5 .5M191.3 81h.5M191.3 80.1h.3M191.4 81.1h.3M191.4 80.8h.5"/>
<path d="M191.4 80.2h.1M191.5 81.3h.2M191.6 81.4h.1M191.7 80.6h.3M192 80.5h.1M192 80.5l-1.4 1.4M192 80.5l-.4 .9M192 80.5l-.9 .4M196.2 90.3h2.5M199.4 80.1h1.2M201.3 80.1h7.6M201.3 85.2h7.6"/>
<path d="M203.8 90.3h5.1M226.7 90.3h5.1M236.8 90.3h5.1M239.4 82.7v2.5M241.9 80.9l.5 .5M241.9 80.9h.7M242 81h.6M242.1 80.1h.3M242.2 81.1h.3M242.2 80.8h.5M242.2 80.2h.1M242.3 81.3h.2"/>
<path d="M242.4 81.4h.1M242.5 80.6h.2M242.7 80.5h.1M242.8 80.5l-1.4 1.4M242.8 80.5l-.4 .9M242.8 80.5l-.9 .4M247 90.3h2.5M250.2 80.1h1.2M252.1 80.1h7.6M252.1 85.2h7.6M254.6 90.3h5.1M18.4 102.3h3.8"/>
<path d="M33.7 103v5.1M33.7 110.6v2.5M36.1 107.7h.7M36.2 107.8h.6M36.2 108.8l.9-.4-.4 .9zM36.3 108.9h.6M36.3 107.9h.4M36.4 108.8h.6M36.4 109h.5M36.4 107.5h.5M36.4 108h.3M36.5 109.1h.3"/>
<path d="M36.6 108.1h.1M36.6 109.2h.2M36.6 108.6h.4M36.7 107.4h.2M36.9 108.5h.2M37 107.3h.1M37 107.3l-1.4 1.4M37 107.3l-.4 .9-.5-.5M37 107.3l-.9 .4M37.1 108.4l-1.4 1.4M41.3 103h7.6M41.3 108.1h7.6"/>
<path d="M43.8 113.1h5.1M71.8 103v5.1M71.8 110.6v2.5M74.2 107.7h.7M74.3 107.8h.6M74.3 108.8l.9-.4-.4 .9zM74.4 108.9h.6M74.4 107.9h.4M74.5 108.8h.6M74.5 109h.5M74.5 107.5h.5M74.5 108h.3"/>
<path d="M74.6 109.1h.3M74.7 108.1h.1M74.7 109.2h.1M74.7 108.6h.4M74.8 107.4h.2M75 108.5h.2M75 107.3h.1M75.1 107.3l-1.4 1.4M75.1 107.3l-.4 .9-.5-.5M75.1 107.3l-.9 .4M75.2 108.4l-1.4 1.4M79.4 103h7.6"/>
<path d="M79.4 108.1h7.6M81.9 113.1h5.1M120 110.6h7.6M120 115.7h7.6M122.6 103h5M175.9 115.7h5.1M186.1 115.7h5M188.6 100.4v5.1M188.6 108.1v2.5M191 105.1h.7M191 105.1l.5 .5M191.1 105.3h.6"/>
<path d="M191.1 106.3l.9-.4-.4 .9zM191.2 106.3h.6M191.2 105.4h.4M191.3 106.2h.6M191.3 105h.5M191.3 106.5h.5M191.4 105.5h.2M191.4 106.6h.3M191.5 105.6h.1M191.5 106.1h.4M191.6 106.7h.1M191.6 104.9h.2"/>
<path d="M191.8 106h.2M191.9 104.8h.1M191.9 104.8l-1.4 1.4M191.9 104.8l-.4 .8M191.9 104.8l-.9 .3M192 105.9l-1.4 1.4M196.2 115.7h2.5M199.4 105.5h1.2M200 104.9v1.3M201.3 105.5h7.6M201.3 110.6h7.6M203.8 115.7h5.1"/>
<path d="M226.7 115.7h5.1M236.8 115.7h5.1M239.4 100.4v5.1M239.4 108.1v2.5M241.8 105.1l.5 .5M241.8 105.1h.7M241.9 106.3l.9-.4-.4 .9zM241.9 105.3h.6M242 106.3h.6M242 105.4h.4M242.1 106.2h.6M242.1 105h.5"/>
<path d="M242.1 106.5h.5M242.1 105.5h.3M242.2 106.6h.3M242.3 105.6h.1M242.3 106.7h.2M242.3 106.1h.4M242.4 104.9h.2M242.6 106h.2M242.6 104.8h.1M242.7 104.8l-1.4 1.4M242.7 104.8l-.4 .8M242.7 104.8l-.9 .3"/>
<path d="M242.8 105.9l-1.4 1.4M247 115.7h2.5M250.2 105.5h1.2M250.8 104.9v1.3M252.1 105.5h7.6M252.1 110.6h7.6M254.6 115.7h5.1M274.9 102.3h3.8M33.7 120.8v5M33.7 128.4v2.5M33.7 138.5v5.1M36.1 125.5l.9-.4-.4 .9z"/>
<path d="M36.2 125.5h.6M36.2 126.6l.5 .5M36.2 126.6h.7M36.2 125.4h.6M36.3 125.6h.4M36.3 126.7h.6M36.4 125.8h.3M36.5 126.9h.3M36.5 126.5h.5M36.5 125.3h.4M36.5 125.9h.1M36.6 127h.2"/>
<path d="M36.7 127.1h.1M36.7 126.4h.3M36.8 125.2h.1M37 125.1l-1.4 1.4M37 126.2h.1M37.1 126.2l-1.4 1.4M37.1 126.2l-.4 .9M37.1 126.2l-.9 .4M41.3 120.8h7.6M41.3 125.8h7.6M41.3 138.5h7.6M43.8 130.9h5.1"/>
<path d="M71.8 120.8v5M71.8 128.4v2.5M71.8 138.5v5.1M74.2 125.5l.9-.4-.4 .9zM74.3 125.5h.6M74.3 125.4h.6M74.3 126.6h.7M74.3 126.6l.5 .5M74.4 125.6h.4M74.4 126.7h.6M74.5 125.8h.3M74.5 126.9h.4"/>
<path d="M74.6 126.5h.5M74.6 125.3h.4M74.6 125.9h.1M74.7 127h.2M74.8 127.1h.1M74.8 126.4h.3M74.9 125.2h.1M75.1 125.1l-1.4 1.4M75.1 126.2h.1M75.2 126.2l-1.4 1.4M75.2 126.2l-.4 .9M75.2 126.2l-.9 .4"/>
<path d="M79.4 120.8h7.6M79.4 125.8h7.6M79.4 138.5h7.6M81.9 130.9h5.1M109.9 136v5.1M122.6 130.9h5M122.6 136h5M122.6 120.8h5M122.6 125.8h5M188.6 125.8v5.1M188.6 133.5v2.5M191.1 130.6h.6"/>
<path d="M191.1 131.7h.8M191.2 130.5h.5M191.2 130.7h.4M191.2 131.8h.6M191.3 130.8h.3M191.4 131.9h.3M191.4 130.9h.1M191.4 131.6h.5M191.4 130.3h.4M191.5 132h.2M191.6 132.1h.1M191.7 131.4h.3"/>
<path d="M191.7 130.2h.2M191.9 130.2l-1.4 1.4M191.9 130.2l-.4 .8-.5-.5M191.9 130.2l-.9 .3M192 131.3h.1M192 131.3l-1.4 1.4M192 131.3l-.4 .9-.5-.5M192 131.3l-.9 .4M199.4 130.9h1.2M200 130.3v1.3M201.3 130.9h7.6M201.3 136h7.6"/>
<path d="M239.4 125.8v5.1M239.4 133.5v2.5M241.8 130.5l.9-.3-.4 .8zM241.9 130.6h.6M241.9 131.7h.7M241.9 130.5h.6M242 130.7h.4M242 131.8h.6M242.1 130.8h.3M242.1 131.9h.4M242.2 130.9h.1M242.2 131.6h.5"/>
<path d="M242.2 130.3h.4M242.3 132h.2M242.4 132.1h.1M242.5 131.4h.2M242.5 130.2h.2M242.7 130.2l-1.4 1.4M242.8 131.3h.1M242.8 131.3l-1.4 1.4M242.8 131.3l-.4 .9-.5-.5M242.8 131.3l-.9 .4M250.2 130.9h1.2M250.8 130.3v1.3"/>
<path d="M252.1 130.9h7.6M252.1 136h7.6M18.4 145.2h3.8M33.7 146.2v2.5M33.7 156.3v5.1M36.1 143.2l.9-.3-.4 .8zM36.1 143.3h.7M36.2 144.4l.9-.4-.4 .9zM36.2 143.4h.5M36.3 144.5h.6M36.3 144.3h.7M36.3 143.1h.6"/>
<path d="M36.3 143.5h.4M36.4 144.6h.5M36.5 143.6h.1M36.5 144.7h.3M36.6 144.2h.4M36.6 143.7h.1M36.6 143h.3M36.7 144.8h.1M36.9 144.1h.2M36.9 142.9h.1M37 142.9l-1.4 1.4M37.1 144l-1.4 1.4"/>
<path d="M41.3 156.3h7.6M41.3 143.6h7.6M43.8 148.7h5.1M71.8 146.2v2.5M71.8 156.3v5.1M74.2 143.2l.9-.3-.4 .8zM74.2 143.3h.7M74.3 143.4h.5M74.3 144.4l.9-.4-.4 .9zM74.4 144.3h.7M74.4 144.5h.6M74.4 143.1h.6"/>
<path d="M74.4 143.5h.4M74.5 144.6h.5M74.6 143.6h.1M74.6 144.7h.3M74.7 144.2h.4M74.7 143.7h.1M74.7 143h.3M74.8 144.8h.1M75 144.1h.1M75 142.9h.1M75.1 142.9l-1.4 1.4M75.2 144l-1.4 1.4"/>
<path d="M79.4 156.3h7.6M79.4 143.6h7.6M81.9 148.7h5.1M109.9 146.2v5M109.9 153.8v2.5M112.3 150.8l.5 .5M112.3 150.9h.7M112.4 152l.9-.4-.4 .9zM112.4 151h.5M112.5 152.1h.6M112.5 151.9h.7M112.5 151.1h.4"/>
<path d="M112.5 150.7h.6M112.6 152.2h.5M112.6 151.2h.2M112.7 152.3h.3M112.8 151.3h.1M112.8 152.4h.1M112.8 151.8h.4M112.8 150.6h.3M113.1 151.7h.1M113.1 150.5h.1M113.2 150.5l-1.4 1.3M113.2 150.5l-.4 .8"/>
<path d="M113.2 150.5l-.9 .3M113.3 151.6l-1.4 1.4M120 146.2h7.6M120 151.2h7.6M122.6 156.3h5M147.3 157.6h1.3M148 156.9v1.3M148 158.8v5.1M160.7 156.3v2.5M172.7 157.6h1.3M173.4 156.9v1.3M173.4 158.8v5.1"/>
<path d="M175.9 141.1h5.1M186.1 141.1h5M196.2 141.1h2.5M203.8 141.1h5.1M226.7 141.1h5.1M236.8 141.1h5.1M247 141.1h2.5M254.6 141.1h5.1M274.9 145.2h3.8M33.7 163.9v2.6M33.7 174.1v5.1M36.1 161l.9-.4-.4 .9z"/>
<path d="M36.1 178.8l.9-.4-.4 .9zM36.1 161h.7M36.1 178.8h.7M36.2 161.1h.6M36.2 162.1l.9-.3-.4 .8zM36.2 179.9l.5 .5M36.2 179.9h.7M36.2 178.7h.7M36.3 162.2h.6M36.3 178.9h.4M36.3 161.2h.4M36.4 162.3h.5"/>
<path d="M36.4 179.1h.3M36.4 162.1h.6M36.4 161.3h.3M36.4 160.9h.5M36.5 162.4h.3M36.5 179.2h.1M36.5 179.8h.5M36.5 178.6h.4M36.6 161.5h.1M36.6 162.5h.2M36.7 161.9h.3M36.7 160.7h.2"/>
<path d="M36.8 179.7h.2M36.8 178.5h.1M37 161.8h.1M37 160.6l-1.4 1.4M37 178.4l-1.4 1.4M37.1 179.6h.1M37.1 161.8l-1.4 1.4M37.1 179.5l-1.4 1.4M37.1 179.5l-.4 .9M37.1 179.5l-.9 .4M41.3 174.1h7.6M41.3 179.2h7.6"/>
<path d="M41.3 161.4h7.6M43.8 166.5h5.1M71.8 163.9v2.6M71.8 174.1v5.1M74.2 178.8l.9-.4-.4 .9zM74.2 161h.7M74.2 178.8h.7M74.3 161.1h.6M74.3 179.9h.7M74.3 179.9l.5 .5M74.3 162.1l.9-.3-.4 .8zM74.3 162.2h.7"/>
<path d="M74.3 178.7h.6M74.4 178.9h.4M74.4 161.2h.4M74.5 162.3h.5M74.5 179.1h.3M74.5 162.1h.6M74.5 160.9h.5M74.5 161.3h.3M74.6 162.4h.3M74.6 179.8h.5M74.6 179.2h.1M74.6 178.6h.4"/>
<path d="M74.6 161.5h.1M74.7 162.5h.2M74.8 161.9h.3M74.8 160.7h.2M74.9 179.7h.2M74.9 178.5h.1M75.1 161.8h.1M75.1 178.4l-1.4 1.4M75.1 160.6l-1.4 1.4M75.1 160.6l-.4 .9-.5-.5M75.1 160.6l-.9 .4M75.2 179.6h.1"/>
<path d="M75.2 179.5l-1.4 1.4M75.2 179.5l-.4 .9M75.2 179.5l-.9 .4M75.2 161.8l-1.4 1.4M79.4 174.1h7.6M79.4 179.2h7.6M79.4 161.4h7.6M81.9 166.5h5.1M109.9 163.9v5.1M109.9 174.1v5.1M112.3 178.8l.9-.4-.4 .9zM112.3 178.8h.7"/>
<path d="M112.4 179.9h.7M112.4 178.9h.5M112.4 178.7h.6M112.6 179.1h.3M112.7 179.8h.5M112.7 179.2h.1M112.7 178.6h.4M113 179.7h.2M113 178.5h.1M113.2 178.4l-1.4 1.4M113.3 179.6h.1M113.3 179.5l-1.4 1.4"/>
<path d="M113.3 179.5l-.4 .9M113.3 179.5l-.9 .4 .5 .5M120 174.1h7.6M120 179.2h7.6M144.5 166.1h.1M144.6 165.9h.3M144.7 165.8h.5M144.7 165.7h.7M144.7 167.1h.2M144.7 165.6h.6M144.7 167h.5M144.8 165.4h.4"/>
<path d="M144.8 166.9h.6M144.8 165.3h.2M144.8 166.8h.7M144.9 165.2h.1M144.9 166.6h.5M144.9 166.5h.3M145 166.4h.1M145 166.3l.5 .5-.8 .4zM145.4 165.7l-.5-.5-.4 .9M145.4 165.7l-.9 .4M145.9 164.7l-1.4 1.4M146 165.8l-1.3 1.4"/>
<path d="M148 166.5v5M148 176.6v5.1M157.2 166.1h.1M157.3 165.9h.3M157.3 165.8h.6M157.4 165.7h.7M157.4 167.1h.2M157.4 165.6h.6M157.4 167h.4M157.5 165.4h.4M157.5 166.9h.6M157.5 165.3h.2"/>
<path d="M157.5 166.8h.7M157.6 166.6h.5M157.6 166.5h.3M157.7 166.4h.1M157.7 166.3l.5 .5-.8 .4zM158.1 165.7l-.5-.5-.4 .9M158.1 165.7l-.9 .4M158.6 164.7l-1.4 1.4M158.7 165.8l-1.3 1.4M160.7 161.4v2.5M160.7 166.5v5M160.7 176.6v5.1"/>
<path d="M169.9 166.1h.1M170 165.9h.3M170 165.8h.6M170.1 165.7h.7M170.1 167.1h.2M170.1 165.6h.6M170.1 167h.4M170.2 165.4h.3M170.2 166.9h.6M170.2 165.3h.2M170.2 166.8h.7M170.3 166.6h.4"/>
<path d="M170.3 165.2l.5 .5-.9 .4zM170.3 166.5h.3M170.4 166.4h.1M170.4 166.3l.5 .5-.8 .4zM171.3 164.7l-1.4 1.4M171.4 165.8l-1.3 1.4M173.4 166.5v5M173.4 176.6v5.1M233.7 167.7v20.3M233.7 177.9h41.2M233.7 172.8h41.2M274.9 167.7h-95.2v20.3"/>
<path d="M33.7 181.7v2.5M36.3 180h.6M36.4 180.1h.4M36.6 180.3h.2M36.7 180.4h.1M43.8 184.2h5.1M64.4 188v3.9M71.8 181.7v2.5M74.4 180h.6M74.5 180.1h.4M74.7 180.3h.2M74.8 180.4h.1"/>
<path d="M81.9 184.2h5.1M106.5 188v3.9M109.9 181.7v2.5M112.5 180h.6M112.6 180.1h.4M112.8 180.3h.2M112.9 180.4h.1M122.6 184.2h5M148.6 188v3.9M190.7 188v3.9M232.8 188v3.9M233.7 183h41.2"/>
<path d="M264.8 183v5"/>
</g>
<path d="M18.4 12.8h260.3v179.1h-260.3z" fill="none" stroke="#c90d0c" stroke-width=".32"/>
<g fill="none" stroke="#c90d0c" stroke-width=".25">
<path d="M38.8 31.9h1.2M40 31.9l2.6-1.3v2.5zM40.7 30.6h-.7v2.5M42.6 31.9h1.2M42.6 34.4h2.5l-1.3 1.3zM55.3 34.4h2.5l-1.3 1.3zM94.6 33.7v2.5l-1.3-1.3zM95.9 24.1l1.3-1.9 1.2 1.9M114.9 28.6l1.3 1.2-1.3 1.3zM114.9 38.7l1.3 1.3-1.3 1.3zM155.6 37h5.1M155.6 38.8a4 4 0 0 1 5 0"/>
<path d="M160.7 29.3h5M160.7 27.5l.9 .5 1.6 .3M163.2 20.4l1.3 1.3h-2.6zM165.7 27.5l-1 .5-1.5 .3M230.5 31.2l1.3-1.9 1.2 1.9M234.3 34.4v5.1M236.2 34.5a4 4 0 0 0 0 4.9M241.9 35.7l1.3 1.3-1.3 1.2zM255.9 34.4l1.3-1.3v2.6zM36.2 59.8h5.1M56.5 59.8h5.1M58.4 56l-1.9 1.3 1.9 1.2"/>
<path d="M78.7 43.8l-1.8 1.3 1.8 1.3M94.6 54v2.5l-1.3-1.3zM114.9 46.4l1.3 1.2-1.3 1.3zM114.9 59.1l1.3 1.2-1.3 1.3zM134 49.7l1.3-1.3v2.5zM140.3 47.1v5.1M141.4 49.7l.2 1.5 .6 .9M142.2 47.2l-.6 .9-.3 1.6M145.4 42h5.1M145.5 43.9a4.1 4.1 0 0 1 5 0M236.8 48.4l2.6 1.3-2.6 1.2zM239.4 48.4v2.5"/>
<path d="M241 52.2h1.8v5.1h-1.8zM244.5 45.8l2.5 1.3-2.5 1.3zM247 45.8v2.6M248.3 59.8h2.5l-1.3 1.3zM248.6 49.7h1.8v5h-1.8zM38.8 60.8l1 .1 1.4 .8M38.8 60.8l-1.1 .2-1.4 .7M40 67.4h2.6l-1.3 1.3zM59.1 60.8l1 .1 1.5 .8M59.1 60.8l-1.6 .3-.9 .6M60.3 67.4h2.6l-1.3 1.3zM81.3 78.8l-1.9 1.3 1.9 1.3"/>
<path d="M87 77.6h5.1v20.3h-5.1zM95.9 75.5h2.5l-1.2 1.3zM114.9 64.1l1.3 1.3-1.3 1.3zM121.9 76.3l-1.9 1.3 1.9 1.2M127.6 75h5.1v30.5h-5.1zM188.6 73.8l1.3 1.2h-2.6zM208.9 77.6h5.1v15.2h-5.1zM239.4 73.8l1.2 1.2h-2.5zM240.6 62.4h2.6l-1.3 1.2zM259.7 77.6h5.1v15.2h-5.1zM32.4 90.3h2.5M33.7 90.3l1.2 2.5h-2.5z"/>
<path d="M33.7 83.9l1.2 1.3h-2.5zM41.3 89v2.5l-1.3-1.2zM43.2 83.9l-1.9 1.3 1.9 1.3M48.9 82.7h5.1v15.2h-5.1zM79.4 83.9v2.6l-1.3-1.3zM120 81.4v2.5l-1.3-1.2zM175.9 89v2.5l-1.3-1.2zM181 89.4h5.1v1.8h-5.1zM187.3 80.1h2.6M188.6 99.2l1.3 1.2h-2.6zM188.6 80.1l1.3 2.6h-2.6zM191.1 89.4h5.1v1.8h-5.1z"/>
<path d="M201.3 83.9v2.6l-1.3-1.3zM226.7 89v2.5l-1.3-1.2zM231.8 89.4h5v1.8h-5zM238.1 80.1h2.5M239.4 99.2l1.2 1.2h-2.5zM239.4 80.1l1.2 2.6h-2.5zM241.9 89.4h5.1v1.8h-5.1zM252.1 83.9v2.6l-1.3-1.3zM32.4 108.1h2.5M33.7 101.7l1.2 1.3h-2.5zM33.7 108.1l1.2 2.5h-2.5zM33.7 119.5l1.2 1.3h-2.5z"/>
<path d="M41.3 106.8v2.5l-1.3-1.2zM43.2 101.7l-1.9 1.3 1.9 1.2M43.2 119.5l-1.9 1.3 1.9 1.2M48.9 118.2h5.1v15.3h-5.1zM48.9 100.4h5.1v15.3h-5.1zM70.5 108.1h2.5M71.8 101.7l1.2 1.3h-2.5zM71.8 108.1l1.2 2.5h-2.5zM71.8 119.5l1.2 1.3h-2.5zM79.4 106.8v2.5l-1.3-1.2zM81.3 101.7l-1.9 1.3 1.9 1.2M81.3 119.5l-1.9 1.3 1.9 1.2"/>
<path d="M87 118.2h5.1v15.3h-5.1zM87 100.4h5.1v15.3h-5.1zM120 114.4v2.5l-1.3-1.2zM121.9 109.3l-1.9 1.3 1.9 1.3M127.6 108.1h5.1v30.4h-5.1zM175.9 114.4v2.5l-1.3-1.2zM181 114.8h5.1v1.8h-5.1zM187.3 105.5h2.6M188.6 105.5l1.3 2.6h-2.6zM191.1 114.8h5.1v1.8h-5.1zM201.3 109.3v2.6l-1.3-1.3zM208.9 103h5.1v15.2h-5.1z"/>
<path d="M226.7 114.4v2.5l-1.3-1.2zM231.8 114.8h5v1.8h-5zM238.1 105.5h2.5M239.4 105.5l1.2 2.6h-2.5zM241.9 114.8h5.1v1.8h-5.1zM252.1 109.3v2.6l-1.3-1.3zM259.7 103h5.1v15.2h-5.1zM32.4 125.8h2.5M33.7 125.8l1.2 2.6h-2.5zM33.7 137.3l1.2 1.2h-2.5zM41.3 124.6v2.5l-1.3-1.3zM43.2 137.3l-1.9 1.2 1.9 1.3"/>
<path d="M48.9 136h5.1v15.2h-5.1zM70.5 125.8h2.5M71.8 125.8l1.2 2.6h-2.5zM71.8 137.3l1.2 1.2h-2.5zM79.4 124.6v2.5l-1.3-1.3zM81.3 137.3l-1.9 1.2 1.9 1.3M87 136h5.1v15.2h-5.1zM109.9 134.7l1.2 1.3h-2.5zM187.3 130.9h2.6M188.6 124.6l1.3 1.2h-2.6zM188.6 130.9l1.3 2.6h-2.6zM200 136l1.3-1.3v2.6z"/>
<path d="M208.9 128.4h5.1v15.2h-5.1zM226.7 139.8v2.5l-1.3-1.2zM238.1 130.9h2.5M239.4 130.9l1.2 2.6h-2.5zM239.4 124.6l1.2 1.2h-2.5zM252.1 134.7v2.6l-1.3-1.3zM259.7 128.4h5.1v15.2h-5.1zM32.4 143.6h2.5M33.7 143.6l1.2 2.6h-2.5zM33.7 155l1.2 1.3h-2.5zM40 143.6l1.3-1.3v2.6zM43.2 155l-1.9 1.3 1.9 1.3"/>
<path d="M48.9 153.8h5.1v15.2h-5.1zM70.5 143.6h2.5M71.8 143.6l1.2 2.6h-2.5zM71.8 155l1.2 1.3h-2.5zM79.4 142.3v2.6l-1.3-1.3zM81.3 155l-1.9 1.3 1.9 1.3M87 153.8h5.1v15.2h-5.1zM108.6 151.2h2.5M109 141.1h1.7v5.1h-1.7zM109.9 151.2l1.2 2.6h-2.5zM118.7 151.2l1.3-1.2v2.5zM121.9 144.9l-1.9 1.3 1.9 1.2"/>
<path d="M127.6 143.6h5.1v15.2h-5.1zM159.4 158.2l1.3-1.9 1.2 1.9M174.6 141.1l1.3-1.3v2.5zM181 140.2h5.1v1.8h-5.1zM191.1 140.2h5.1v1.8h-5.1zM231.8 140.2h5v1.8h-5zM241.9 140.2h5.1v1.8h-5.1zM32.4 161.4h2.5M32.4 179.2h2.5M33.7 161.4l1.2 2.5h-2.5zM33.7 179.2l1.2 2.5h-2.5zM33.7 172.8l1.2 1.3h-2.5z"/>
<path d="M41.3 160.1v2.5l-1.3-1.2zM41.3 177.9v2.5l-1.3-1.2zM43.2 172.8l-1.9 1.3 1.9 1.2M48.9 171.5h5.1v15.3h-5.1zM70.5 161.4h2.5M70.5 179.2h2.5M71.8 161.4l1.2 2.5h-2.5zM71.8 179.2l1.2 2.5h-2.5zM71.8 172.8l1.2 1.3h-2.5zM79.4 160.1v2.5l-1.3-1.2zM79.4 177.9v2.5l-1.3-1.2zM81.3 172.8l-1.9 1.3 1.9 1.2"/>
<path d="M87 171.5h5.1v15.3h-5.1zM108.6 179.2h2.5M109 169h1.7v5.1h-1.7zM109.9 162.6l1.2 1.3h-2.5zM109.9 179.2l1.2 2.5h-2.5zM120 177.9v2.5l-1.3-1.2zM121.9 172.8l-1.9 1.3 1.9 1.2M127.6 171.5h5.1v15.3h-5.1zM146.7 163.9h2.5l-1.2 2.6zM146.7 166.5h2.5M147.1 171.5h1.7v5.1h-1.7zM159.4 166.5h2.5"/>
<path d="M159.4 163.9h2.5l-1.2 2.6zM159.8 171.5h1.7v5.1h-1.7zM172.1 166.5h2.5M172.1 163.9h2.5l-1.2 2.6zM172.5 171.5h1.7v5.1h-1.7zM146.7 181.7h2.5l-1.2 1.3zM159.4 181.7h2.5l-1.2 1.3zM172.1 181.7h2.5l-1.2 1.3z"/>
<circle cx="38.8" cy="35.7" r="1.27"/>
<circle cx="51.5" cy="35.7" r="1.27"/>
<circle cx="112.4" cy="21" r="1.27"/>
<circle cx="34.9" cy="57.3" r="1.27"/>
<circle cx="200" cy="80.1" r="1.27"/>
<circle cx="250.8" cy="80.1" r="1.27"/>
<circle cx="200" cy="105.5" r="1.27"/>
<circle cx="250.8" cy="105.5" r="1.27"/>
<circle cx="200" cy="130.9" r="1.27"/>
<circle cx="250.8" cy="130.9" r="1.27"/>
<circle cx="148" cy="157.6" r="1.27"/>
<circle cx="173.4" cy="157.6" r="1.27"/>
</g>
<path d="M101 22.2h7.6v53.3h-7.6z" fill="none" stroke="#c90d0c" stroke-width=".42"/>
<g fill="#c90d0c" stroke="#c90d0c" stroke-width=".21">
<path d="M102.3 29.3l.6-.2v.2a.51 .51 0 0 0-.5 .5 .51 .51 0 0 0 .5 .6v.2a.76 .76 0 0 1-.7-.5 .76 .76 0 0 1 .1-.8z" fill-rule="evenodd"/>
<path d="M102.3 26.8l.6-.3v.3a.51 .51 0 0 0-.5 .5 .51 .51 0 0 0 .5 .5v.3a.76 .76 0 0 1-.7-.5 .76 .76 0 0 1 .1-.8z" fill-rule="evenodd"/>
<path d="M102.3 24.2l.6-.2v.3a.51 .51 0 0 0-.5 .5 .51 .51 0 0 0 .5 .5v.2a.76 .76 0 0 1-.7-.4 .76 .76 0 0 1 .1-.9z" fill-rule="evenodd"/>
<path d="M106.7 29.1a.76 .76 0 0 1 .8 .7 .76 .76 0 0 1-.8 .8v-.2a.51 .51 0 0 0 .5-.6 .51 .51 0 0 0-.5-.5z" fill-rule="evenodd"/>
<path d="M106.7 26.5a.76 .76 0 0 1 .8 .8 .76 .76 0 0 1-.8 .8v-.3a.51 .51 0 0 0 .5-.5 .51 .51 0 0 0-.5-.5z" fill-rule="evenodd"/>
<path d="M106.7 24a.76 .76 0 0 1 .8 .8 .76 .76 0 0 1-.8 .7v-.2a.51 .51 0 0 0 .5-.5 .51 .51 0 0 0-.5-.5z" fill-rule="evenodd"/>
<path d="M102.3 34.4l.6-.2v.2a.51 .51 0 0 0-.5 .5 .51 .51 0 0 0 .5 .5v.3a.77 .77 0 0 1-.7-.5 .77 .77 0 0 1 .1-.8z" fill-rule="evenodd"/>
<path d="M102.3 31.8l.6-.2v.3a.51 .51 0 0 0-.5 .5 .51 .51 0 0 0 .5 .5v.2a.77 .77 0 0 1-.7-.4 .77 .77 0 0 1 .1-.9z" fill-rule="evenodd"/>
<path d="M106.7 34.2a.76 .76 0 0 1 .8 .7 .76 .76 0 0 1-.8 .8v-.3a.51 .51 0 0 0 .5-.5 .51 .51 0 0 0-.5-.5z" fill-rule="evenodd"/>
<path d="M106.7 31.6a.76 .76 0 0 1 .8 .8 .76 .76 0 0 1-.8 .7v-.2a.51 .51 0 0 0 .5-.5 .51 .51 0 0 0-.5-.5z" fill-rule="evenodd"/>
<path d="M102.3 42l.6-.2v.2a.51 .51 0 0 0-.5 .5 .51 .51 0 0 0 .5 .6v.2a.77 .77 0 0 1-.7-.5 .77 .77 0 0 1 .1-.8z" fill-rule="evenodd"/>
<path d="M102.3 39.5l.6-.3v.3a.51 .51 0 0 0-.5 .5 .51 .51 0 0 0 .5 .5v.3a.77 .77 0 0 1-.7-.5 .77 .77 0 0 1 .1-.8z" fill-rule="evenodd"/>
<path d="M102.3 36.9l.6-.2v.3a.51 .51 0 0 0-.5 .5 .51 .51 0 0 0 .5 .5v.2a.77 .77 0 0 1-.7-.5 .77 .77 0 0 1 .1-.8z" fill-rule="evenodd"/>
<path d="M106.7 41.8a.76 .76 0 0 1 .8 .7 .76 .76 0 0 1-.8 .8v-.2a.51 .51 0 0 0 .5-.6 .51 .51 0 0 0-.5-.5z" fill-rule="evenodd"/>
<path d="M106.7 39.2a.76 .76 0 0 1 .8 .8 .76 .76 0 0 1-.8 .8v-.3a.51 .51 0 0 0 .5-.5 .51 .51 0 0 0-.5-.5z" fill-rule="evenodd"/>
<path d="M106.7 36.7a.76 .76 0 0 1 .8 .8 .76 .76 0 0 1-.8 .7v-.2a.51 .51 0 0 0 .5-.5 .51 .51 0 0 0-.5-.5z" fill-rule="evenodd"/>
<path d="M102.3 47.1l.6-.2v.2a.51 .51 0 0 0-.5 .5 .51 .51 0 0 0 .5 .5v.3a.77 .77 0 0 1-.7-.5 .77 .77 0 0 1 .1-.8z" fill-rule="evenodd"/>
<path d="M102.3 44.5l.6-.2v.3a.51 .51 0 0 0-.5 .5 .51 .51 0 0 0 .5 .5v.2a.77 .77 0 0 1-.7-.4 .77 .77 0 0 1 .1-.9z" fill-rule="evenodd"/>
<path d="M106.7 46.9a.76 .76 0 0 1 .8 .7 .76 .76 0 0 1-.8 .8v-.3a.51 .51 0 0 0 .5-.5 .51 .51 0 0 0-.5-.5z" fill-rule="evenodd"/>
<path d="M106.7 44.3a.76 .76 0 0 1 .8 .8 .76 .76 0 0 1-.8 .7v-.2a.51 .51 0 0 0 .5-.5 .51 .51 0 0 0-.5-.5z" fill-rule="evenodd"/>
<path d="M102.3 54.7l.6-.2v.2a.51 .51 0 0 0-.5 .5 .51 .51 0 0 0 .5 .6v.2a.77 .77 0 0 1-.7-.5 .77 .77 0 0 1 .1-.8z" fill-rule="evenodd"/>
<path d="M102.3 52.2l.6-.3v.3a.51 .51 0 0 0-.5 .5 .51 .51 0 0 0 .5 .5v.3a.77 .77 0 0 1-.7-.5 .77 .77 0 0 1 .1-.8z" fill-rule="evenodd"/>
<path d="M102.3 49.6l.6-.2v.3a.51 .51 0 0 0-.5 .5 .51 .51 0 0 0 .5 .5v.2a.77 .77 0 0 1-.7-.5 .77 .77 0 0 1 .1-.8z" fill-rule="evenodd"/>
<path d="M106.7 54.5a.76 .76 0 0 1 .8 .7 .76 .76 0 0 1-.8 .8v-.2a.51 .51 0 0 0 .5-.6 .51 .51 0 0 0-.5-.5z" fill-rule="evenodd"/>
<path d="M106.7 51.9a.76 .76 0 0 1 .8 .8 .76 .76 0 0 1-.8 .8v-.3a.51 .51 0 0 0 .5-.5 .51 .51 0 0 0-.5-.5z" fill-rule="evenodd"/>
<path d="M106.7 49.4a.76 .76 0 0 1 .8 .8 .76 .76 0 0 1-.8 .7v-.2a.51 .51 0 0 0 .5-.5 .51 .51 0 0 0-.5-.5z" fill-rule="evenodd"/>
<path d="M102.3 59.8l.6-.2v.2a.51 .51 0 0 0-.5 .5 .51 .51 0 0 0 .5 .5v.3a.77 .77 0 0 1-.7-.5 .77 .77 0 0 1 .1-.8z" fill-rule="evenodd"/>
<path d="M102.3 57.2l.6-.2v.3a.51 .51 0 0 0-.5 .5 .51 .51 0 0 0 .5 .5v.2a.77 .77 0 0 1-.7-.4 .77 .77 0 0 1 .1-.9z" fill-rule="evenodd"/>
<path d="M106.7 59.6a.76 .76 0 0 1 .8 .7 .76 .76 0 0 1-.8 .8v-.3a.51 .51 0 0 0 .5-.5 .51 .51 0 0 0-.5-.5z" fill-rule="evenodd"/>
<path d="M106.7 57a.76 .76 0 0 1 .8 .8 .76 .76 0 0 1-.8 .7v-.2a.51 .51 0 0 0 .5-.5 .51 .51 0 0 0-.5-.5z" fill-rule="evenodd"/>
<path d="M102.3 64.9l.6-.3v.3a.51 .51 0 0 0-.5 .5 .51 .51 0 0 0 .5 .5v.3a.77 .77 0 0 1-.7-.5 .77 .77 0 0 1 .1-.8z" fill-rule="evenodd"/>
<path d="M102.3 62.3l.6-.2v.3a.51 .51 0 0 0-.5 .5 .51 .51 0 0 0 .5 .5v.2a.77 .77 0 0 1-.7-.5 .77 .77 0 0 1 .1-.8z" fill-rule="evenodd"/>
<path d="M106.7 64.6a.76 .76 0 0 1 .8 .8 .76 .76 0 0 1-.8 .8v-.3a.51 .51 0 0 0 .5-.5 .51 .51 0 0 0-.5-.5z" fill-rule="evenodd"/>
<path d="M106.7 62.1a.76 .76 0 0 1 .8 .8 .76 .76 0 0 1-.8 .7v-.2a.51 .51 0 0 0 .5-.5 .51 .51 0 0 0-.5-.5z" fill-rule="evenodd"/>
<path d="M102.3 72.5l.6-.3v.3a.51 .51 0 0 0-.5 .5 .51 .51 0 0 0 .5 .5v.3a.75 .75 0 0 1-.7-.5 .75 .75 0 0 1 .1-.8z" fill-rule="evenodd"/>
<path d="M102.3 69.9l.6-.2v.3a.51 .51 0 0 0-.5 .5 .51 .51 0 0 0 .5 .5v.2a.75 .75 0 0 1-.7-.4 .75 .75 0 0 1 .1-.9z" fill-rule="evenodd"/>
<path d="M102.3 67.4l.6-.2v.2a.5 .5 0 0 0-.5 .5 .5 .5 0 0 0 .5 .5v.3a.75 .75 0 0 1-.7-.5 .75 .75 0 0 1 .1-.8z" fill-rule="evenodd"/>
<path d="M106.7 72.2a.76 .76 0 0 1 .7 .8 .76 .76 0 0 1-.7 .8v-.3a.51 .51 0 0 0 .5-.5 .51 .51 0 0 0-.5-.5z" fill-rule="evenodd"/>
<path d="M106.7 69.7a.76 .76 0 0 1 .7 .8 .76 .76 0 0 1-.7 .7v-.2a.51 .51 0 0 0 .5-.5 .51 .51 0 0 0-.5-.5z" fill-rule="evenodd"/>
<path d="M106.7 67.2a.75 .75 0 0 1 .8 .7 .75 .75 0 0 1-.8 .8v-.3a.5 .5 0 0 0 .5-.5 .5 .5 0 0 0-.5-.5z" fill-rule="evenodd"/>
<path d="M262.4 23.5l.7-.3v.3a.76 .76 0 0 0-.7 .8 .76 .76 0 0 0 .7 .7v.3a1.02 1.02 0 0 1-.9-.7 1.02 1.02 0 0 1 .2-1.1z" fill-rule="evenodd"/>
<path d="M262.4 26l.7-.2v.2a.76 .76 0 0 0-.7 .8 .76 .76 0 0 0 .7 .8v.2a1.02 1.02 0 0 1-.9-.6 1.02 1.02 0 0 1 .2-1.2z" fill-rule="evenodd"/>
<path d="M262.4 28.6l.7-.3v.3a.76 .76 0 0 0-.7 .7 .76 .76 0 0 0 .7 .8v.3a1.02 1.02 0 0 1-.9-.7 1.02 1.02 0 0 1 .2-1.1z" fill-rule="evenodd"/>
<path d="M262.4 31.1l.7-.2v.2a.76 .76 0 0 0-.7 .8 .76 .76 0 0 0 .7 .7v.3a1.02 1.02 0 0 1-.9-.7 1.02 1.02 0 0 1 .2-1.1z" fill-rule="evenodd"/>
<path d="M262.4 33.6l.7-.2v.3a.76 .76 0 0 0-.7 .7 .76 .76 0 0 0 .7 .8v.2a1.02 1.02 0 0 1-.9-.6 1.02 1.02 0 0 1 .2-1.2z" fill-rule="evenodd"/>
<path d="M262.4 36.2l.7-.3v.3a.76 .76 0 0 0-.7 .8 .76 .76 0 0 0 .7 .7v.3a1.02 1.02 0 0 1-.9-.7 1.02 1.02 0 0 1 .2-1.1z" fill-rule="evenodd"/>
<path d="M262.4 38.7l.7-.2v.2a.76 .76 0 0 0-.7 .8 .76 .76 0 0 0 .7 .8v.2a1.02 1.02 0 0 1-.9-.6 1.02 1.02 0 0 1 .2-1.2z" fill-rule="evenodd"/>
<path d="M262.4 41.3l.7-.3v.3a.76 .76 0 0 0-.7 .7 .76 .76 0 0 0 .7 .8v.3a1.02 1.02 0 0 1-.9-.7 1.02 1.02 0 0 1 .2-1.1z" fill-rule="evenodd"/>
<path d="M262.4 43.8l.7-.2v.2a.76 .76 0 0 0-.7 .8 .76 .76 0 0 0 .7 .7v.3a1.02 1.02 0 0 1-.9-.7 1.02 1.02 0 0 1 .2-1.1z" fill-rule="evenodd"/>
</g>
<g fill="none" stroke="#0dab76" stroke-width=".21">
<path d="M89.5 32.4h7.7M89.5 27.3h7.7M89.5 29.8h7.7M89.5 37.5h7.7M112.4 24.8v2.5M112.4 32.4h7.6M112.4 34.9h7.6M112.4 37.5h7.6M148 39.5h5v5.1h12.7M158.1 34.4h7.6v2.6M163.2 31.9v7.6h2.5M231.8 31.9v5.1"/>
<path d="M239.4 37v2.5h-7.6M259.7 26.8h-12.7v15.2h-15.2M259.7 29.3h-10.2v15.3h-17.7M43.8 57.3v7.6h-5M64.2 57.3v7.6h-5.1M79.4 45.1h17.8M89.5 50.2h7.7M89.5 42.5h7.7M89.5 57.8h7.7M89.5 47.6h7.7M89.5 52.7h7.7M89.5 40h7.7"/>
<path d="M112.4 45.1h7.6M112.4 50.2h7.6M112.4 42.5h7.6M112.4 57.8h7.6M112.4 52.7h7.6M112.4 55.2h7.6M145.4 49.7h20.3M148 47.1h17.7M158.1 42h7.6M231.8 49.7h2.5M231.8 47.1h10.1M89.5 65.4h7.7"/>
<path d="M89.5 60.3h7.7M89.5 67.9h7.7M89.5 70.5h7.7M89.5 62.9h7.7M112.4 73h7.6M112.4 67.9h7.6M112.4 70.5h7.6M112.4 62.9h7.6M33.7 95.4h10.1M79.4 90.3h2.5M79.4 95.4h2.5M120 92.8h2.6"/>
<path d="M120 97.9h2.6M120 87.7h2.6M188.6 85.2v5.1M198.7 90.3h5.1M239.4 85.2v5.1M249.5 90.3h5.1M33.7 113.1h10.1M71.8 113.1h10.1M120 103h2.6M188.6 110.6v5.1M198.7 115.7h5.1M239.4 110.6v5.1"/>
<path d="M249.5 115.7h5.1M33.7 130.9h10.1M71.8 130.9h10.1M120 130.9h2.6M120 125.8h2.6M120 120.8h2.6M120 136h2.6M188.6 136v5.1M239.4 136v5.1M33.7 148.7h10.1M71.8 148.7h10.1M109.9 156.3h12.7"/>
<path d="M160.7 158.8v2.6M198.7 141.1h5.1M249.5 141.1h5.1M33.7 166.5h10.1M71.8 166.5h10.1M33.7 184.2h10.1M71.8 184.2h10.1M109.9 184.2h12.7"/>
</g>
<g fill="#0dab76" stroke="#0dab76" stroke-width=".21">
<circle cx="231.8" cy="37" r=".51"/>
<circle cx="59.1" cy="57.3" r=".51"/>
<circle cx="112.4" cy="24.8" r=".51"/>
<circle cx="38.8" cy="31.9" r=".51"/>
<circle cx="38.8" cy="57.3" r=".51"/>
<circle cx="239.4" cy="37" r=".51"/>
<circle cx="43.8" cy="31.9" r=".51"/>
<circle cx="41.3" cy="64.9" r=".51"/>
<circle cx="61.6" cy="64.9" r=".51"/>
<circle cx="188.6" cy="141.1" r=".51"/>
<circle cx="188.6" cy="90.3" r=".51"/>
<circle cx="188.6" cy="115.7" r=".51"/>
<circle cx="239.4" cy="90.3" r=".51"/>
<circle cx="239.4" cy="115.7" r=".51"/>
<circle cx="239.4" cy="141.1" r=".51"/>
</g>
<use href="#words"/>
</svg>
